VERSION 5.7 ;
BUSBITCHARS "[]" ;
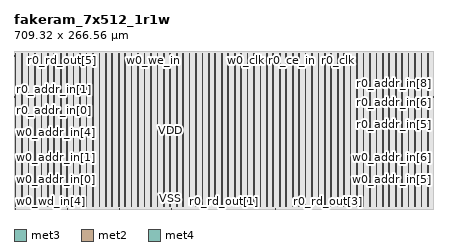
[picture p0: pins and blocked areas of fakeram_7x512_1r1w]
MACRO fakeram_7x512_1r1w
  FOREIGN fakeram_7x512_1r1w 0 0 ;
  SYMMETRY X Y R90 ;
  SIZE 709.320 BY 266.560 ;
  CLASS BLOCK ;
  PIN w0_wd_in[0]
    DIRECTION INPUT ;
    USE SIGNAL ;
    SHAPE ABUTMENT ;
    PORT
      LAYER met3 ;
      RECT 0.000 3.930 0.900 4.230 ;
    END
  END w0_wd_in[0]
  PIN w0_wd_in[1]
    DIRECTION INPUT ;
    USE SIGNAL ;
    SHAPE ABUTMENT ;
    PORT
      LAYER met3 ;
      RECT 0.000 27.050 0.900 27.350 ;
    END
  END w0_wd_in[1]
  PIN w0_wd_in[2]
    DIRECTION INPUT ;
    USE SIGNAL ;
    SHAPE ABUTMENT ;
    PORT
      LAYER met3 ;
      RECT 708.420 3.930 709.320 4.230 ;
    END
  END w0_wd_in[2]
  PIN w0_wd_in[3]
    DIRECTION INPUT ;
    USE SIGNAL ;
    SHAPE ABUTMENT ;
    PORT
      LAYER met3 ;
      RECT 708.420 27.050 709.320 27.350 ;
    END
  END w0_wd_in[3]
  PIN w0_wd_in[4]
    DIRECTION OUTPUT ;
    USE SIGNAL ;
    SHAPE ABUTMENT ;
    PORT
      LAYER met2 ;
      RECT 2.690 0.000 2.830 0.420 ;
    END
  END w0_wd_in[4]
  PIN w0_wd_in[5]
    DIRECTION OUTPUT ;
    USE SIGNAL ;
    SHAPE ABUTMENT ;
    PORT
      LAYER met2 ;
      RECT 90.550 0.000 90.690 0.420 ;
    END
  END w0_wd_in[5]
  PIN w0_wd_in[6]
    DIRECTION OUTPUT ;
    USE SIGNAL ;
    SHAPE ABUTMENT ;
    PORT
      LAYER met2 ;
      RECT 178.410 0.000 178.550 0.420 ;
    END
  END w0_wd_in[6]
  PIN r0_rd_out[0]
    DIRECTION OUTPUT ;
    USE SIGNAL ;
    SHAPE ABUTMENT ;
    PORT
      LAYER met2 ;
      RECT 266.270 0.000 266.410 0.420 ;
    END
  END r0_rd_out[0]
  PIN r0_rd_out[1]
    DIRECTION OUTPUT ;
    USE SIGNAL ;
    SHAPE ABUTMENT ;
    PORT
      LAYER met2 ;
      RECT 354.130 0.000 354.270 0.420 ;
    END
  END r0_rd_out[1]
  PIN r0_rd_out[2]
    DIRECTION OUTPUT ;
    USE SIGNAL ;
    SHAPE ABUTMENT ;
    PORT
      LAYER met2 ;
      RECT 441.990 0.000 442.130 0.420 ;
    END
  END r0_rd_out[2]
  PIN r0_rd_out[3]
    DIRECTION OUTPUT ;
    USE SIGNAL ;
    SHAPE ABUTMENT ;
    PORT
      LAYER met2 ;
      RECT 529.850 0.000 529.990 0.420 ;
    END
  END r0_rd_out[3]
  PIN r0_rd_out[4]
    DIRECTION OUTPUT ;
    USE SIGNAL ;
    SHAPE ABUTMENT ;
    PORT
      LAYER met2 ;
      RECT 2.690 266.140 2.830 266.560 ;
    END
  END r0_rd_out[4]
  PIN r0_rd_out[5]
    DIRECTION OUTPUT ;
    USE SIGNAL ;
    SHAPE ABUTMENT ;
    PORT
      LAYER met2 ;
      RECT 80.430 266.140 80.570 266.560 ;
    END
  END r0_rd_out[5]
  PIN r0_rd_out[6]
    DIRECTION OUTPUT ;
    USE SIGNAL ;
    SHAPE ABUTMENT ;
    PORT
      LAYER met2 ;
      RECT 158.170 266.140 158.310 266.560 ;
    END
  END r0_rd_out[6]
  PIN w0_addr_in[0]
    DIRECTION INPUT ;
    USE SIGNAL ;
    SHAPE ABUTMENT ;
    PORT
      LAYER met3 ;
      RECT 0.000 50.170 0.900 50.470 ;
    END
  END w0_addr_in[0]
  PIN w0_addr_in[1]
    DIRECTION INPUT ;
    USE SIGNAL ;
    SHAPE ABUTMENT ;
    PORT
      LAYER met3 ;
      RECT 0.000 73.290 0.900 73.590 ;
    END
  END w0_addr_in[1]
  PIN w0_addr_in[2]
    DIRECTION INPUT ;
    USE SIGNAL ;
    SHAPE ABUTMENT ;
    PORT
      LAYER met3 ;
      RECT 0.000 96.410 0.900 96.710 ;
    END
  END w0_addr_in[2]
  PIN w0_addr_in[3]
    DIRECTION INPUT ;
    USE SIGNAL ;
    SHAPE ABUTMENT ;
    PORT
      LAYER met3 ;
      RECT 0.000 119.530 0.900 119.830 ;
    END
  END w0_addr_in[3]
  PIN w0_addr_in[4]
    DIRECTION INPUT ;
    USE SIGNAL ;
    SHAPE ABUTMENT ;
    PORT
      LAYER met3 ;
      RECT 0.000 142.650 0.900 142.950 ;
    END
  END w0_addr_in[4]
  PIN w0_addr_in[5]
    DIRECTION INPUT ;
    USE SIGNAL ;
    SHAPE ABUTMENT ;
    PORT
      LAYER met3 ;
      RECT 708.420 50.170 709.320 50.470 ;
    END
  END w0_addr_in[5]
  PIN w0_addr_in[6]
    DIRECTION INPUT ;
    USE SIGNAL ;
    SHAPE ABUTMENT ;
    PORT
      LAYER met3 ;
      RECT 708.420 73.290 709.320 73.590 ;
    END
  END w0_addr_in[6]
  PIN w0_addr_in[7]
    DIRECTION INPUT ;
    USE SIGNAL ;
    SHAPE ABUTMENT ;
    PORT
      LAYER met3 ;
      RECT 708.420 96.410 709.320 96.710 ;
    END
  END w0_addr_in[7]
  PIN w0_addr_in[8]
    DIRECTION INPUT ;
    USE SIGNAL ;
    SHAPE ABUTMENT ;
    PORT
      LAYER met3 ;
      RECT 708.420 119.530 709.320 119.830 ;
    END
  END w0_addr_in[8]
  PIN r0_addr_in[0]
    DIRECTION INPUT ;
    USE SIGNAL ;
    SHAPE ABUTMENT ;
    PORT
      LAYER met3 ;
      RECT 0.000 165.770 0.900 166.070 ;
    END
  END r0_addr_in[0]
  PIN r0_addr_in[1]
    DIRECTION INPUT ;
    USE SIGNAL ;
    SHAPE ABUTMENT ;
    PORT
      LAYER met3 ;
      RECT 0.000 188.890 0.900 189.190 ;
    END
  END r0_addr_in[1]
  PIN r0_addr_in[2]
    DIRECTION INPUT ;
    USE SIGNAL ;
    SHAPE ABUTMENT ;
    PORT
      LAYER met3 ;
      RECT 0.000 212.010 0.900 212.310 ;
    END
  END r0_addr_in[2]
  PIN r0_addr_in[3]
    DIRECTION INPUT ;
    USE SIGNAL ;
    SHAPE ABUTMENT ;
    PORT
      LAYER met3 ;
      RECT 0.000 235.130 0.900 235.430 ;
    END
  END r0_addr_in[3]
  PIN r0_addr_in[4]
    DIRECTION INPUT ;
    USE SIGNAL ;
    SHAPE ABUTMENT ;
    PORT
      LAYER met3 ;
      RECT 0.000 258.250 0.900 258.550 ;
    END
  END r0_addr_in[4]
  PIN r0_addr_in[5]
    DIRECTION INPUT ;
    USE SIGNAL ;
    SHAPE ABUTMENT ;
    PORT
      LAYER met3 ;
      RECT 708.420 142.650 709.320 142.950 ;
    END
  END r0_addr_in[5]
  PIN r0_addr_in[6]
    DIRECTION INPUT ;
    USE SIGNAL ;
    SHAPE ABUTMENT ;
    PORT
      LAYER met3 ;
      RECT 708.420 165.770 709.320 166.070 ;
    END
  END r0_addr_in[6]
  PIN r0_addr_in[7]
    DIRECTION INPUT ;
    USE SIGNAL ;
    SHAPE ABUTMENT ;
    PORT
      LAYER met3 ;
      RECT 708.420 188.890 709.320 189.190 ;
    END
  END r0_addr_in[7]
  PIN r0_addr_in[8]
    DIRECTION INPUT ;
    USE SIGNAL ;
    SHAPE ABUTMENT ;
    PORT
      LAYER met3 ;
      RECT 708.420 212.010 709.320 212.310 ;
    END
  END r0_addr_in[8]
  PIN w0_we_in
    DIRECTION INPUT ;
    USE SIGNAL ;
    SHAPE ABUTMENT ;
    PORT
      LAYER met2 ;
      RECT 235.910 266.140 236.050 266.560 ;
    END
  END w0_we_in
  PIN w0_ce_in
    DIRECTION INPUT ;
    USE SIGNAL ;
    SHAPE ABUTMENT ;
    PORT
      LAYER met2 ;
      RECT 313.650 266.140 313.790 266.560 ;
    END
  END w0_ce_in
  PIN w0_clk
    DIRECTION INPUT ;
    USE SIGNAL ;
    SHAPE ABUTMENT ;
    PORT
      LAYER met2 ;
      RECT 391.390 266.140 391.530 266.560 ;
    END
  END w0_clk
  PIN r0_ce_in
    DIRECTION INPUT ;
    USE SIGNAL ;
    SHAPE ABUTMENT ;
    PORT
      LAYER met2 ;
      RECT 469.130 266.140 469.270 266.560 ;
    END
  END r0_ce_in
  PIN r0_clk
    DIRECTION INPUT ;
    USE SIGNAL ;
    SHAPE ABUTMENT ;
    PORT
      LAYER met2 ;
      RECT 546.870 266.140 547.010 266.560 ;
    END
  END r0_clk
  PIN VSS
    DIRECTION INOUT ;
    USE GROUND ;
    PORT
      LAYER met4 ;
      RECT 2.160 4.080 3.360 262.480 ;
      RECT 13.040 4.080 14.240 262.480 ;
      RECT 23.920 4.080 25.120 262.480 ;
      RECT 34.800 4.080 36.000 262.480 ;
      RECT 45.680 4.080 46.880 262.480 ;
      RECT 56.560 4.080 57.760 262.480 ;
      RECT 67.440 4.080 68.640 262.480 ;
      RECT 78.320 4.080 79.520 262.480 ;
      RECT 89.200 4.080 90.400 262.480 ;
      RECT 100.080 4.080 101.280 262.480 ;
      RECT 110.960 4.080 112.160 262.480 ;
      RECT 121.840 4.080 123.040 262.480 ;
      RECT 132.720 4.080 133.920 262.480 ;
      RECT 143.600 4.080 144.800 262.480 ;
      RECT 154.480 4.080 155.680 262.480 ;
      RECT 165.360 4.080 166.560 262.480 ;
      RECT 176.240 4.080 177.440 262.480 ;
      RECT 187.120 4.080 188.320 262.480 ;
      RECT 198.000 4.080 199.200 262.480 ;
      RECT 208.880 4.080 210.080 262.480 ;
      RECT 219.760 4.080 220.960 262.480 ;
      RECT 230.640 4.080 231.840 262.480 ;
      RECT 241.520 4.080 242.720 262.480 ;
      RECT 252.400 4.080 253.600 262.480 ;
      RECT 263.280 4.080 264.480 262.480 ;
      RECT 274.160 4.080 275.360 262.480 ;
      RECT 285.040 4.080 286.240 262.480 ;
      RECT 295.920 4.080 297.120 262.480 ;
      RECT 306.800 4.080 308.000 262.480 ;
      RECT 317.680 4.080 318.880 262.480 ;
      RECT 328.560 4.080 329.760 262.480 ;
      RECT 339.440 4.080 340.640 262.480 ;
      RECT 350.320 4.080 351.520 262.480 ;
      RECT 361.200 4.080 362.400 262.480 ;
      RECT 372.080 4.080 373.280 262.480 ;
      RECT 382.960 4.080 384.160 262.480 ;
      RECT 393.840 4.080 395.040 262.480 ;
      RECT 404.720 4.080 405.920 262.480 ;
      RECT 415.600 4.080 416.800 262.480 ;
      RECT 426.480 4.080 427.680 262.480 ;
      RECT 437.360 4.080 438.560 262.480 ;
      RECT 448.240 4.080 449.440 262.480 ;
      RECT 459.120 4.080 460.320 262.480 ;
      RECT 470.000 4.080 471.200 262.480 ;
      RECT 480.880 4.080 482.080 262.480 ;
      RECT 491.760 4.080 492.960 262.480 ;
      RECT 502.640 4.080 503.840 262.480 ;
      RECT 513.520 4.080 514.720 262.480 ;
      RECT 524.400 4.080 525.600 262.480 ;
      RECT 535.280 4.080 536.480 262.480 ;
      RECT 546.160 4.080 547.360 262.480 ;
      RECT 557.040 4.080 558.240 262.480 ;
      RECT 567.920 4.080 569.120 262.480 ;
      RECT 578.800 4.080 580.000 262.480 ;
      RECT 589.680 4.080 590.880 262.480 ;
      RECT 600.560 4.080 601.760 262.480 ;
      RECT 611.440 4.080 612.640 262.480 ;
      RECT 622.320 4.080 623.520 262.480 ;
      RECT 633.200 4.080 634.400 262.480 ;
      RECT 644.080 4.080 645.280 262.480 ;
      RECT 654.960 4.080 656.160 262.480 ;
      RECT 665.840 4.080 667.040 262.480 ;
      RECT 676.720 4.080 677.920 262.480 ;
      RECT 687.600 4.080 688.800 262.480 ;
      RECT 698.480 4.080 699.680 262.480 ;
    END
  END VSS
  PIN VDD
    DIRECTION INOUT ;
    USE POWER ;
    PORT
      LAYER met4 ;
      RECT 2.160 4.080 3.360 262.480 ;
      RECT 13.040 4.080 14.240 262.480 ;
      RECT 23.920 4.080 25.120 262.480 ;
      RECT 34.800 4.080 36.000 262.480 ;
      RECT 45.680 4.080 46.880 262.480 ;
      RECT 56.560 4.080 57.760 262.480 ;
      RECT 67.440 4.080 68.640 262.480 ;
      RECT 78.320 4.080 79.520 262.480 ;
      RECT 89.200 4.080 90.400 262.480 ;
      RECT 100.080 4.080 101.280 262.480 ;
      RECT 110.960 4.080 112.160 262.480 ;
      RECT 121.840 4.080 123.040 262.480 ;
      RECT 132.720 4.080 133.920 262.480 ;
      RECT 143.600 4.080 144.800 262.480 ;
      RECT 154.480 4.080 155.680 262.480 ;
      RECT 165.360 4.080 166.560 262.480 ;
      RECT 176.240 4.080 177.440 262.480 ;
      RECT 187.120 4.080 188.320 262.480 ;
      RECT 198.000 4.080 199.200 262.480 ;
      RECT 208.880 4.080 210.080 262.480 ;
      RECT 219.760 4.080 220.960 262.480 ;
      RECT 230.640 4.080 231.840 262.480 ;
      RECT 241.520 4.080 242.720 262.480 ;
      RECT 252.400 4.080 253.600 262.480 ;
      RECT 263.280 4.080 264.480 262.480 ;
      RECT 274.160 4.080 275.360 262.480 ;
      RECT 285.040 4.080 286.240 262.480 ;
      RECT 295.920 4.080 297.120 262.480 ;
      RECT 306.800 4.080 308.000 262.480 ;
      RECT 317.680 4.080 318.880 262.480 ;
      RECT 328.560 4.080 329.760 262.480 ;
      RECT 339.440 4.080 340.640 262.480 ;
      RECT 350.320 4.080 351.520 262.480 ;
      RECT 361.200 4.080 362.400 262.480 ;
      RECT 372.080 4.080 373.280 262.480 ;
      RECT 382.960 4.080 384.160 262.480 ;
      RECT 393.840 4.080 395.040 262.480 ;
      RECT 404.720 4.080 405.920 262.480 ;
      RECT 415.600 4.080 416.800 262.480 ;
      RECT 426.480 4.080 427.680 262.480 ;
      RECT 437.360 4.080 438.560 262.480 ;
      RECT 448.240 4.080 449.440 262.480 ;
      RECT 459.120 4.080 460.320 262.480 ;
      RECT 470.000 4.080 471.200 262.480 ;
      RECT 480.880 4.080 482.080 262.480 ;
      RECT 491.760 4.080 492.960 262.480 ;
      RECT 502.640 4.080 503.840 262.480 ;
      RECT 513.520 4.080 514.720 262.480 ;
      RECT 524.400 4.080 525.600 262.480 ;
      RECT 535.280 4.080 536.480 262.480 ;
      RECT 546.160 4.080 547.360 262.480 ;
      RECT 557.040 4.080 558.240 262.480 ;
      RECT 567.920 4.080 569.120 262.480 ;
      RECT 578.800 4.080 580.000 262.480 ;
      RECT 589.680 4.080 590.880 262.480 ;
      RECT 600.560 4.080 601.760 262.480 ;
      RECT 611.440 4.080 612.640 262.480 ;
      RECT 622.320 4.080 623.520 262.480 ;
      RECT 633.200 4.080 634.400 262.480 ;
      RECT 644.080 4.080 645.280 262.480 ;
      RECT 654.960 4.080 656.160 262.480 ;
      RECT 665.840 4.080 667.040 262.480 ;
      RECT 676.720 4.080 677.920 262.480 ;
      RECT 687.600 4.080 688.800 262.480 ;
      RECT 698.480 4.080 699.680 262.480 ;
    END
  END VDD
  OBS
    LAYER met1 ;
    RECT 0 0 709.320 266.560 ;
    LAYER met2 ;
    RECT 0 0 709.320 266.560 ;
    LAYER met3 ;
    RECT 0 0 709.320 266.560 ;
    LAYER met4 ;
    RECT 0 0 709.320 266.560 ;
  END
END fakeram_7x512_1r1w

END LIBRARY
